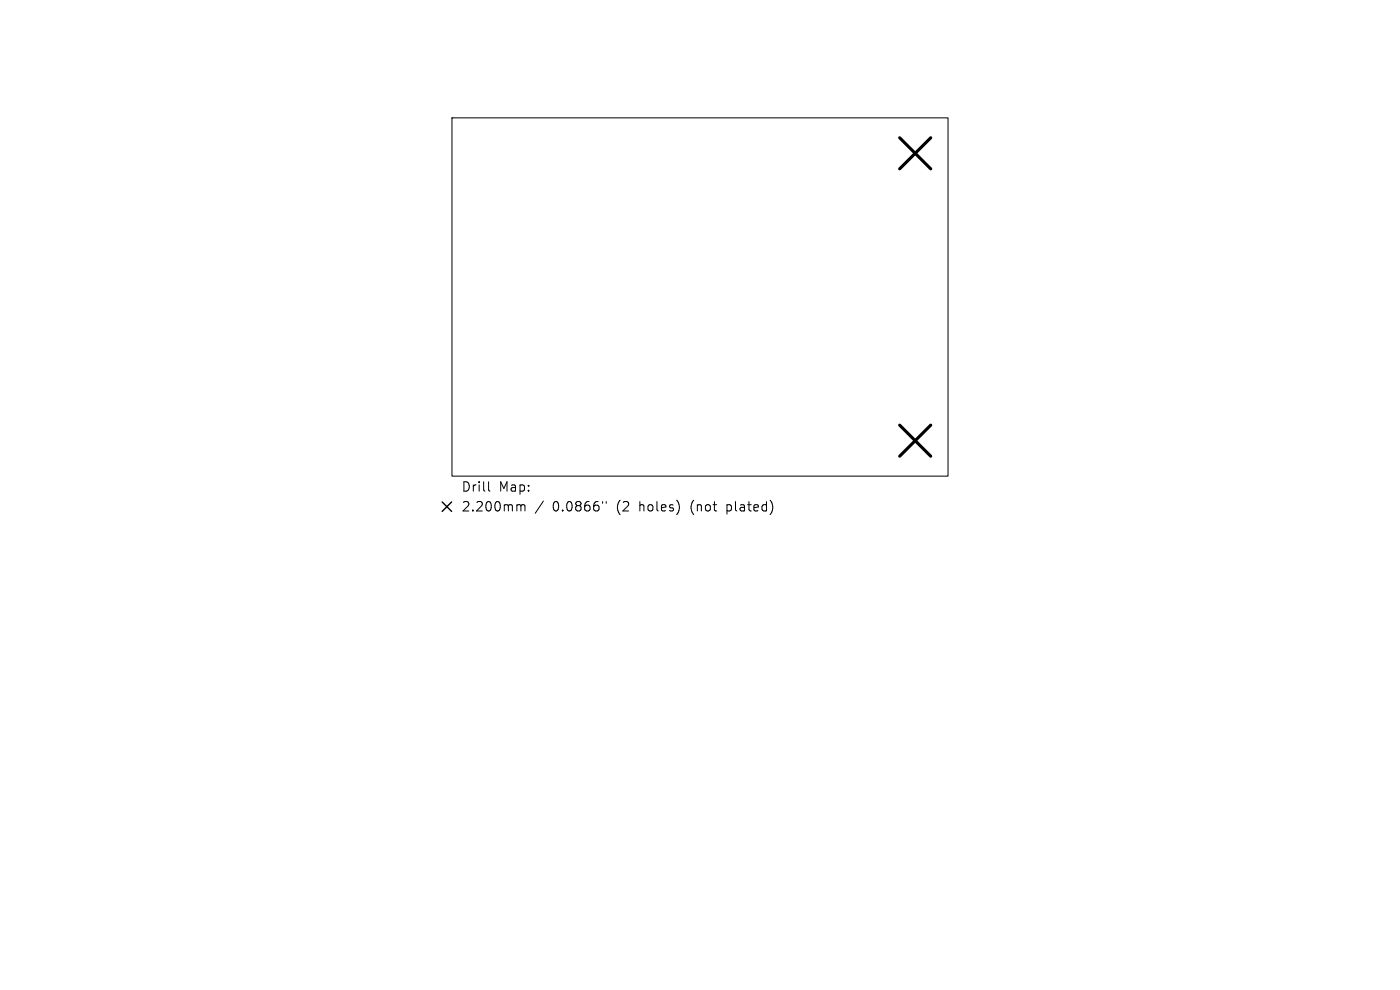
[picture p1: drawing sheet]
<svg xmlns="http://www.w3.org/2000/svg" width="297mm" height="210mm" viewBox="0 0 297 210" stroke-linecap="round" stroke-linejoin="round" font-family="sans-serif">
<defs><g id="words">
<g font-size="2.8">
<text x="97.8" y="104.6">Drill</text>
<text x="105.8" y="104.6">Map:</text>
<text x="97.8" y="108.8">2.200mm</text>
<text x="117.3" y="108.8">0.0866&quot;</text>
<text x="131" y="108.8">(2</text>
<text x="135.9" y="108.8">holes)</text>
<text x="147" y="108.8">(not</text>
<text x="154.8" y="108.8">plated)</text>
</g>
</g></defs>
<path d="M95.9 25h105.2v76h-105.2zM103.7 102.2v1.7l.2 .3M109.9 107.1h.3l.3 .2M110.5 107.3l.3-.2 .5 .1 .1 1.2M110.5 107.3v1.1M115.3 106.3l-1.7 2.6M127.8 106.4v.4M128.6 106.4v.4" fill="none" stroke="#000" stroke-width=".21"/>
<path d="M190.9 29.2l6.6 6.6M197.5 29.2l-6.6 6.6M190.9 90.2l6.6 6.6M197.5 90.2l-6.6 6.6" fill="none" stroke="#000" stroke-width=".66"/>
<path d="M93.8 106.5l2 2M95.8 106.5l-2 2" fill="none" stroke="#000" stroke-width=".3"/>
<use href="#words"/>
</svg>
